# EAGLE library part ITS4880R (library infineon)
Smart Power High-Side-Switch for Industrial Applications. Eight Channels: 8 x 200 mOhm Source: http://www.infineon.com .. ITS4880R_20060309.pdf

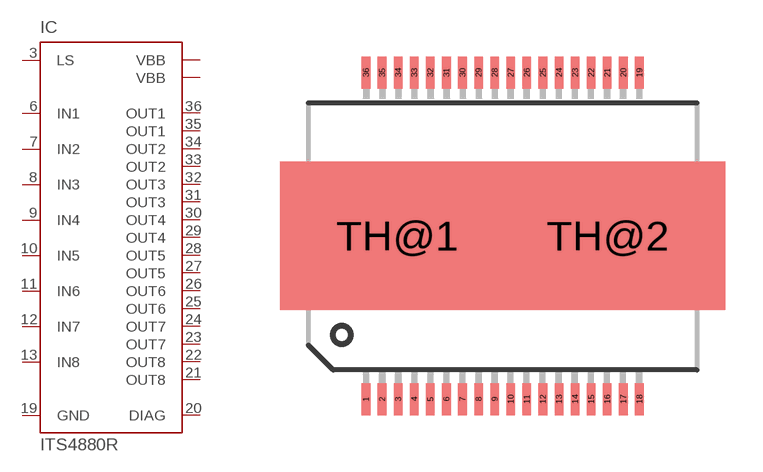
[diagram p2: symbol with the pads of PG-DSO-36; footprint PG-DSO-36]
Designator prefix IC

## ITS4880R (MPN: ITS4880R; OC_FARNELL: 1440818; OC_NEWARK: 58M7534)  [PG-DSO-36]
3  LS  in
6  IN1  in
7  IN2  in
8  IN3  in
9  IN4  in
10  IN5  in
11  IN6  in
12  IN7  in
13  IN8  in
19  GND  pwr
20  DIAG  out
21  OUT8  out
22  OUT8  out
23  OUT7  out
24  OUT7  out
25  OUT6  out
26  OUT6  out
27  OUT5  out
28  OUT5  out
29  OUT4  out
30  OUT4  out
31  OUT3  out
32  OUT3  out
33  OUT2  out
34  OUT2  out
35  OUT1  out
36  OUT1  out
TH@1  VBB  in
TH@2  VBB  in

## Footprint PG-DSO-36 (pad centres in mm)
Smart Power High-Side-Switch for Industrial Applications. Eight Channels: 8 x 200 m? PG-DSO-36 Source: http://www.infineon.com .. ITS4880R_20060309.pdf
smd 0.35 x 1.3: 1 -5.525,-6.6; 2 -4.875,-6.6; 3 -4.225,-6.6; 4 -3.575,-6.6; 5 -2.925,-6.6; 6 -2.275,-6.6; 7 -1.625,-6.6; 8 -0.975,-6.6; 9 -0.325,-6.6; 10 0.325,-6.6; 11 0.975,-6.6; 12 1.625,-6.6; 13 2.275,-6.6; 14 2.925,-6.6; 15 3.575,-6.6; 16 4.225,-6.6; 17 4.875,-6.6; 18 5.525,-6.6; 19 5.525,6.6; 20 4.875,6.6; 21 4.225,6.6; 22 3.575,6.6; 23 2.925,6.6; 24 2.275,6.6; 25 1.625,6.6; 26 0.975,6.6; 27 0.325,6.6; 28 -0.325,6.6; 29 -0.975,6.6; 30 -1.625,6.6; 31 -2.275,6.6; 32 -2.925,6.6; 33 -3.575,6.6; 34 -4.225,6.6; 35 -4.875,6.6; 36 -5.525,6.6
smd 9.5 x 6: TH@1 -4.25,0; TH@2 4.25,0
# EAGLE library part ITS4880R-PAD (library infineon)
Smart Power High-Side-Switch for Industrial Applications. Eight Channels: 8 x 200 mOhm with thermal pad to bottom side Source: http://www.infineon.com .. ITS4880R_20060309.pdf

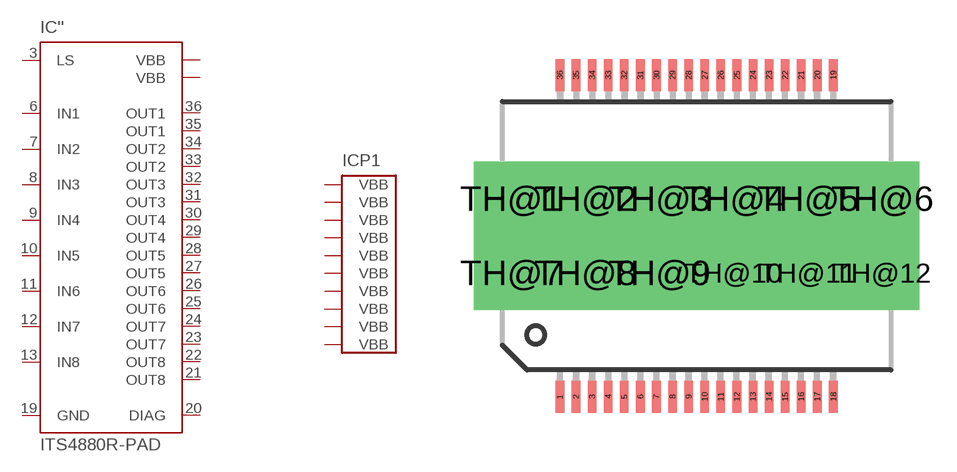
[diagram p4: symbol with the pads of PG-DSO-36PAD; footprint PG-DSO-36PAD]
Designator prefix IC; gates ''=ITS4880R P1=VBB10

## ITS4880R-PAD (OC_FARNELL: unknown; OC_NEWARK: unknown)  [PG-DSO-36PAD]
3  '':LS  in
6  '':IN1  in
7  '':IN2  in
8  '':IN3  in
9  '':IN4  in
10  '':IN5  in
11  '':IN6  in
12  '':IN7  in
13  '':IN8  in
19  '':GND  pwr
20  '':DIAG  out
21  '':OUT8  out
22  '':OUT8  out
23  '':OUT7  out
24  '':OUT7  out
25  '':OUT6  out
26  '':OUT6  out
27  '':OUT5  out
28  '':OUT5  out
29  '':OUT4  out
30  '':OUT4  out
31  '':OUT3  out
32  '':OUT3  out
33  '':OUT2  out
34  '':OUT2  out
35  '':OUT1  out
36  '':OUT1  out
TH@1  '':VBB  in
TH@2  '':VBB  in
TH@3  P1:VBB  pas
TH@4  P1:VBB  pas
TH@5  P1:VBB  pas
TH@6  P1:VBB  pas
TH@7  P1:VBB  pas
TH@8  P1:VBB  pas
TH@9  P1:VBB  pas
TH@10  P1:VBB  pas
TH@11  P1:VBB  pas
TH@12  P1:VBB  pas

## Footprint PG-DSO-36PAD (pad centres in mm)
PG-DSO-36 with thermal on top and bottom Source: http://www.infineon.com .. ITS4880R_20060309.pdf
smd 0.35 x 1.3: 1 -5.525,-6.5; 2 -4.875,-6.5; 3 -4.225,-6.5; 4 -3.575,-6.5; 5 -2.925,-6.5; 6 -2.275,-6.5; 7 -1.625,-6.5; 8 -0.975,-6.5; 9 -0.325,-6.5; 10 0.325,-6.5; 11 0.975,-6.5; 12 1.625,-6.5; 13 2.275,-6.5; 14 2.925,-6.5; 15 3.575,-6.5; 16 4.225,-6.5; 17 4.875,-6.5; 18 5.525,-6.5; 19 5.525,6.5; 20 4.875,6.5; 21 4.225,6.5; 22 3.575,6.5; 23 2.925,6.5; 24 2.275,6.5; 25 1.625,6.5; 26 0.975,6.5; 27 0.325,6.5; 28 -0.325,6.5; 29 -0.975,6.5; 30 -1.625,6.5; 31 -2.275,6.5; 32 -2.925,6.5; 33 -3.575,6.5; 34 -4.225,6.5; 35 -4.875,6.5; 36 -5.525,6.5
drill 0.6 pad 3 square: TH@1 -7.5,1.5; TH@2 -4.5,1.5; TH@3 -1.5,1.5; TH@4 1.5,1.5; TH@5 4.5,1.5; TH@6 7.5,1.5; TH@7 -7.5,-1.5; TH@8 -4.5,-1.5; TH@9 -1.5,-1.5; TH@10 1.5,-1.5; TH@11 4.5,-1.5; TH@12 7.5,-1.5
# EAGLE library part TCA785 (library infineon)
Phase Control IC Source: http://www.infineon.com/ .. tca785.pdf

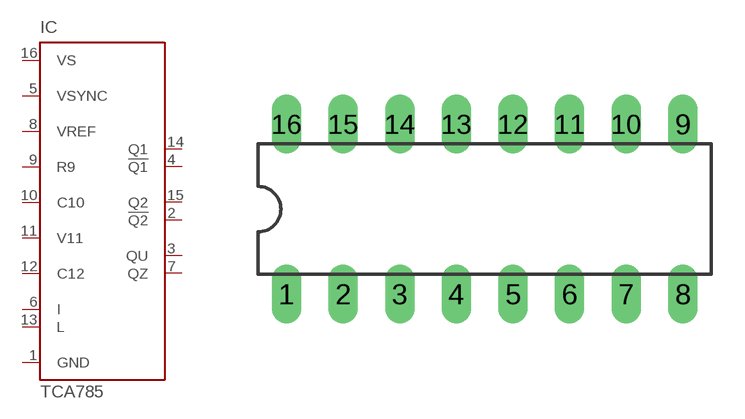
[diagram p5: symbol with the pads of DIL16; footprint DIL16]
Designator prefix IC

## TCA785 (OC_FARNELL: unknown; OC_NEWARK: unknown)  [DIL16]
1  GND  pwr
2  !Q2  out
3  QU  out
4  !Q1  out
5  VSYNC  in
6  I  in
7  QZ  out
8  VREF  in
9  R9  in
10  C10  in
11  V11  in
12  C12  in
13  L  in
14  Q1  out
15  Q2  out
16  VS  in

## Footprint DIL16 (pad centres in mm)
Dual In Line Package
drill 0.813 long: 1 -8.89,-3.81; 2 -6.35,-3.81; 3 -3.81,-3.81; 4 -1.27,-3.81; 5 1.27,-3.81; 6 3.81,-3.81; 7 6.35,-3.81; 8 8.89,-3.81; 9 8.89,3.81; 10 6.35,3.81; 11 3.81,3.81; 12 1.27,3.81; 13 -1.27,3.81; 14 -3.81,3.81; 15 -6.35,3.81; 16 -8.89,3.81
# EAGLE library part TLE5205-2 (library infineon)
5-A H-Bridge for DC-Motor Applications Source: http://www.infineon.com .. tle5205-2.pdf

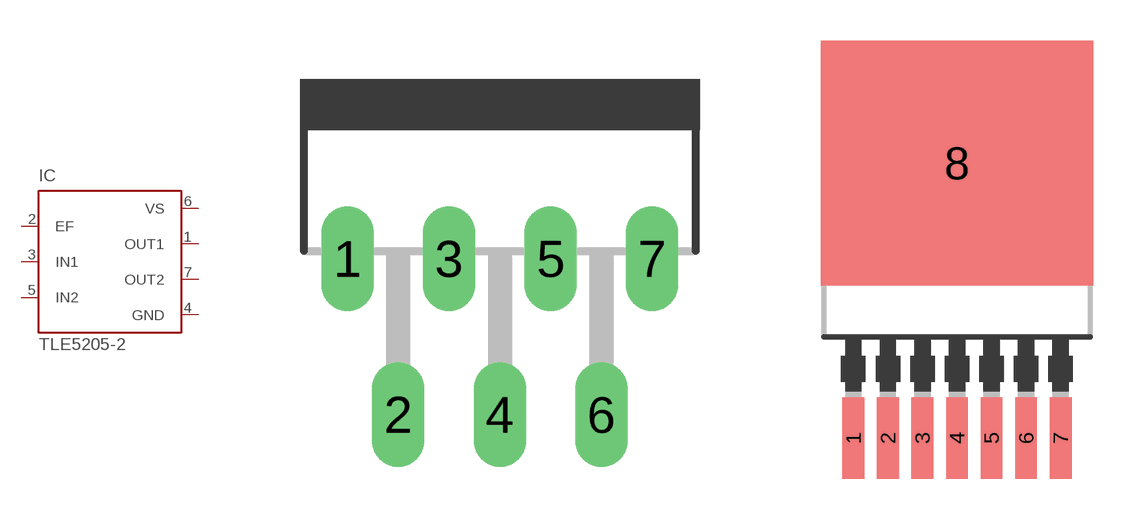
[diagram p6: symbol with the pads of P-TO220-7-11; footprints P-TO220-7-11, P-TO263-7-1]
Designator prefix IC

## TLE5205-2 (OC_FARNELL: unknown; OC_NEWARK: unknown)  [P-TO220-7-11]
1  OUT1  out
2  EF  oc
3  IN1  in
4  GND  pwr
5  IN2  in
6  VS  in
7  OUT2  out

## TLE5205-2G (OC_FARNELL: unknown; OC_NEWARK: unknown)  [P-TO263-7-1]
Pads as for P-TO220-7-11

## TLE5205-2S (OC_FARNELL: unknown; OC_NEWARK: unknown)  [P-TO220-7-12]
Pads as for P-TO220-7-11

## Footprint P-TO220-7-11 (pad centres in mm)
(Plastic Transistor Single Outline Package)P-TO220-7-11 Source: http://www.infineon.com .. tle5205-2.pdf
drill 0.8 pad 1.2 long: 1 -3.81,-1.85; 2 -2.54,-5.75; 3 -1.27,-1.85; 4 0,-5.75; 5 1.27,-1.85; 6 2.54,-5.75; 7 3.81,-1.85

## Footprint P-TO263-7-1 (pad centres in mm)
Plastic Transistor Single Outline Package P-TO263-7-1 Option E3180 Source: http://www.infineon.com .. tle5205-2.pdf
smd 0.8 x 3: 1 -3.81,-9.207; 2 -2.54,-9.207; 3 -1.27,-9.207; 4 0,-9.207; 5 1.27,-9.207; 6 2.54,-9.207; 7 3.81,-9.207
smd 10 x 9: 8 0,0.895

## Footprint P-TO220-7-12 (pad centres in mm)
Plastic Transistor Single Outline PackageP-TO220-7-12 Source: http://www.infineon.com .. tle5205-2.pdf
drill 0.8 pad 0.9 long: 1 -3.81,0; 2 -2.54,0; 3 -1.27,0; 4 0,0; 5 1.27,0; 6 2.54,0; 7 3.81,0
